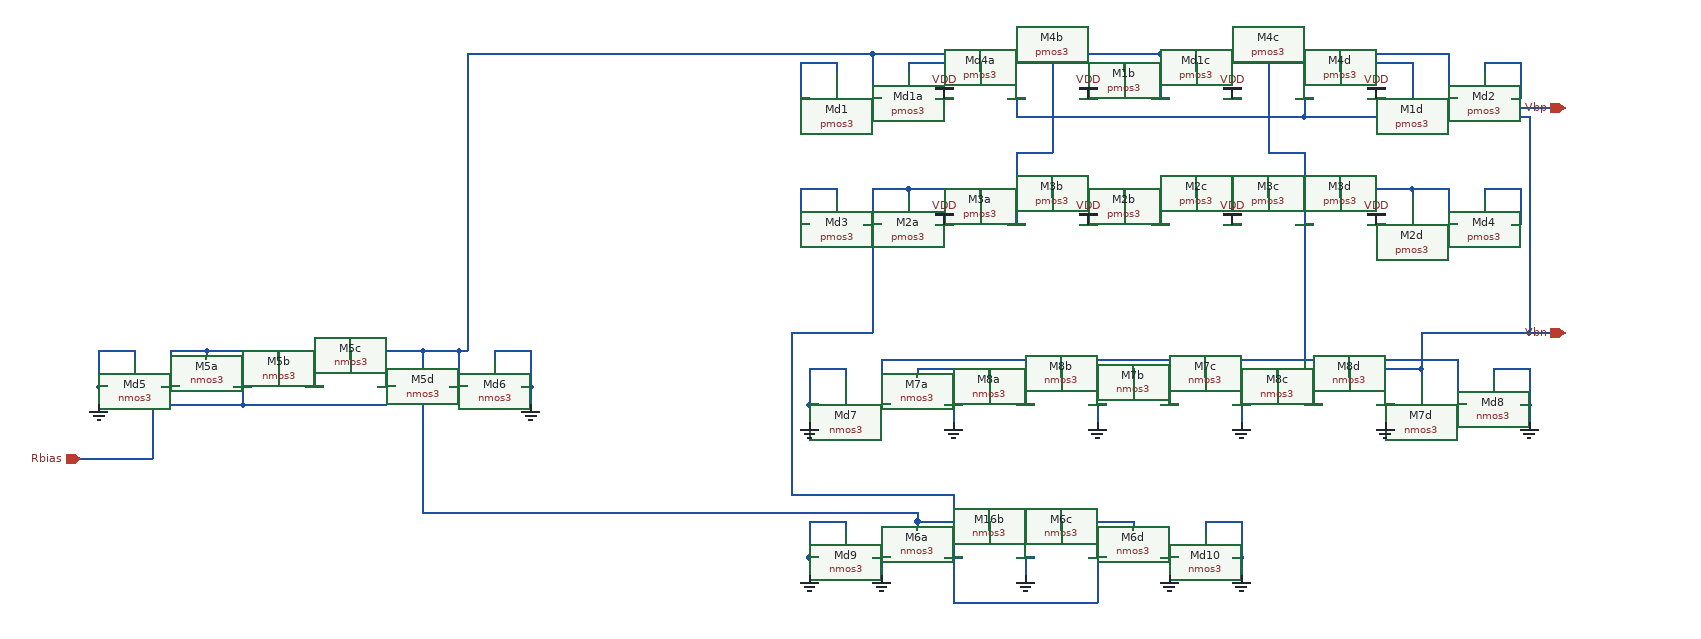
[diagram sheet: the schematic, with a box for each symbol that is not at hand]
v {xschem version=2.9.9 file_version=1.2 }
G {}
K {}
V {}
S {}
E {}
N 660 -1080 680 -1080 { lab=Rbias}
N 580 -1080 600 -1080 { lab=#net1}
N 500 -1080 520 -1080 { lab=Rbias}
N 710 -1120 710 -1110 { lab=#net1}
N 470 -1120 710 -1120 { lab=#net1}
N 470 -1120 470 -1110 { lab=#net1}
N 550 -1120 550 -1110 { lab=#net1}
N 630 -1120 630 -1110 { lab=#net1}
N 670 -1080 670 -1060 { lab=Rbias}
N 510 -1060 670 -1060 { lab=Rbias}
N 510 -1080 510 -1060 { lab=Rbias}
N 410 -1060 510 -1060 { lab=Rbias}
N 430 -1080 440 -1080 { lab=#net1}
N 740 -1080 750 -1080 { lab=#net1}
N 430 -1120 470 -1120 { lab=#net1}
N 430 -1120 430 -1080 { lab=#net1}
N 710 -1120 750 -1120 { lab=#net1}
N 750 -1120 750 -1080 { lab=#net1}
N 590 -1120 590 -1080 { lab=#net1}
N 760 -1210 760 -1120 { lab=#net1}
N 750 -1120 760 -1120 { lab=#net1}
N 750 -1080 760 -1080 { lab=#net1}
N 790 -1120 790 -1110 { lab=GND}
N 790 -1120 830 -1120 { lab=GND}
N 830 -1120 830 -1080 { lab=GND}
N 820 -1080 830 -1080 { lab=GND}
N 830 -1080 830 -1060 { lab=GND}
N 420 -1080 430 -1080 { lab=#net1}
N 390 -1120 390 -1110 { lab=GND}
N 360 -1120 390 -1120 { lab=GND}
N 350 -1080 360 -1080 { lab=GND}
N 350 -1120 360 -1120 { lab=GND}
N 350 -1120 350 -1080 { lab=GND}
N 350 -1080 350 -1060 { lab=GND}
N 410 -1060 410 -1000 { lab=Rbias}
N 330 -1000 410 -1000 { lab=Rbias}
N 1180 -1100 1180 -1090 { lab=GND}
N 1260 -1100 1260 -1090 { lab=Vbp}
N 1340 -1100 1340 -1090 { lab=Vbp}
N 1420 -1100 1420 -1090 { lab=Vbp}
N 1210 -1060 1230 -1060 { lab=Vbp}
N 1290 -1060 1310 -1060 { lab=GND}
N 1370 -1060 1390 -1060 { lab=Vbp}
N 1450 -1060 1470 -1060 { lab=GND}
N 1500 -1100 1500 -1090 { lab=Vbp}
N 1580 -1100 1580 -1090 { lab=Vbp}
N 1660 -1100 1660 -1090 { lab=Vbp}
N 1740 -1100 1740 -1090 { lab=Vbp}
N 1530 -1060 1550 -1060 { lab=Vbp}
N 1610 -1060 1630 -1060 { lab=GND}
N 1690 -1060 1710 -1060 { lab=Vbp}
N 1770 -1060 1790 -1060 { lab=GND}
N 1820 -1100 1820 -1090 { lab=Vbp}
N 1900 -1100 1900 -1090 { lab=GND}
N 1850 -1060 1870 -1060 { lab=Vbp}
N 1260 -1100 1820 -1100 { lab=Vbp}
N 1140 -1100 1180 -1100 { lab=GND}
N 1140 -1100 1140 -1060 { lab=GND}
N 1140 -1060 1150 -1060 { lab=GND}
N 1930 -1060 1940 -1060 { lab=GND}
N 1940 -1100 1940 -1060 { lab=GND}
N 1900 -1100 1940 -1100 { lab=GND}
N 1940 -1060 1940 -1040 { lab=GND}
N 1140 -1060 1140 -1040 { lab=GND}
N 1300 -1060 1300 -1040 { lab=GND}
N 1460 -1060 1460 -1040 { lab=GND}
N 1620 -1060 1620 -1040 { lab=GND}
N 1780 -1060 1780 -1040 { lab=GND}
N 1380 -1100 1380 -1060 { lab=Vbp}
N 1700 -1100 1700 -1060 { lab=Vbp}
N 1220 -1110 1220 -1060 { lab=Vbp}
N 1220 -1110 1860 -1110 { lab=Vbp}
N 1860 -1110 1860 -1060 { lab=Vbp}
N 1540 -1110 1540 -1060 { lab=Vbp}
N 1200 -1400 1220 -1400 { lab=#net1}
N 1280 -1400 1300 -1400 { lab=VDD}
N 1360 -1400 1380 -1400 { lab=Vbp}
N 1440 -1400 1460 -1400 { lab=VDD}
N 1520 -1400 1540 -1400 { lab=#net1}
N 1600 -1400 1620 -1400 { lab=VDD}
N 1680 -1400 1700 -1400 { lab=Vbp}
N 1760 -1400 1780 -1400 { lab=VDD}
N 1840 -1400 1860 -1400 { lab=#net1}
N 1170 -1440 1170 -1430 { lab=#net2}
N 1250 -1440 1250 -1430 { lab=Vbp}
N 1330 -1440 1330 -1430 { lab=Vbp}
N 1410 -1440 1410 -1430 { lab=Vbp}
N 1490 -1440 1490 -1430 { lab=Vbp}
N 1570 -1440 1570 -1430 { lab=Vbp}
N 1650 -1440 1650 -1430 { lab=Vbp}
N 1730 -1440 1730 -1430 { lab=Vbp}
N 1810 -1440 1810 -1430 { lab=Vbp}
N 1890 -1440 1890 -1430 { lab=#net3}
N 1250 -1440 1810 -1440 { lab=Vbp}
N 1890 -1440 1930 -1440 { lab=#net3}
N 1930 -1440 1930 -1400 { lab=#net3}
N 1920 -1400 1930 -1400 { lab=#net3}
N 1130 -1440 1170 -1440 { lab=#net2}
N 1130 -1440 1130 -1400 { lab=#net2}
N 1130 -1400 1140 -1400 { lab=#net2}
N 1200 -1260 1220 -1260 { lab=#net4}
N 1280 -1260 1300 -1260 { lab=VDD}
N 1360 -1260 1380 -1260 { lab=Vbp}
N 1440 -1260 1460 -1260 { lab=VDD}
N 1520 -1260 1540 -1260 { lab=#net4}
N 1600 -1260 1620 -1260 { lab=VDD}
N 1680 -1260 1700 -1260 { lab=Vbp}
N 1760 -1260 1780 -1260 { lab=VDD}
N 1840 -1260 1860 -1260 { lab=#net4}
N 1170 -1300 1170 -1290 { lab=#net5}
N 1250 -1300 1250 -1290 { lab=#net4}
N 1330 -1300 1330 -1290 { lab=#net4}
N 1410 -1300 1410 -1290 { lab=#net4}
N 1490 -1300 1490 -1290 { lab=#net4}
N 1570 -1300 1570 -1290 { lab=#net4}
N 1650 -1300 1650 -1290 { lab=#net4}
N 1730 -1300 1730 -1290 { lab=#net4}
N 1810 -1300 1810 -1290 { lab=#net4}
N 1890 -1300 1890 -1290 { lab=#net6}
N 1250 -1300 1810 -1300 { lab=#net4}
N 1890 -1300 1930 -1300 { lab=#net6}
N 1930 -1300 1930 -1260 { lab=#net6}
N 1920 -1260 1930 -1260 { lab=#net6}
N 1130 -1300 1170 -1300 { lab=#net5}
N 1130 -1300 1130 -1260 { lab=#net5}
N 1130 -1260 1140 -1260 { lab=#net5}
N 1530 -1450 1530 -1400 { lab=#net1}
N 1210 -1450 1530 -1450 { lab=#net1}
N 1210 -1450 1210 -1400 { lab=#net1}
N 1850 -1450 1850 -1400 { lab=#net1}
N 1530 -1450 1850 -1450 { lab=#net1}
N 1530 -1300 1530 -1260 { lab=#net4}
N 1210 -1300 1210 -1260 { lab=#net4}
N 1210 -1300 1250 -1300 { lab=#net4}
N 1850 -1300 1850 -1260 { lab=#net4}
N 1810 -1300 1850 -1300 { lab=#net4}
N 1370 -1340 1370 -1260 { lab=Vbp}
N 1370 -1340 1410 -1340 { lab=Vbp}
N 1410 -1430 1410 -1340 { lab=Vbp}
N 1690 -1340 1690 -1260 { lab=Vbp}
N 1650 -1340 1690 -1340 { lab=Vbp}
N 1650 -1430 1650 -1340 { lab=Vbp}
N 1370 -1400 1370 -1380 { lab=Vbp}
N 1370 -1380 1690 -1380 { lab=Vbp}
N 1690 -1400 1690 -1380 { lab=Vbp}
N 1290 -890 1310 -890 { lab=#net4}
N 1370 -890 1390 -890 { lab=GND}
N 1450 -890 1470 -890 { lab=#net4}
N 1500 -930 1500 -920 { lab=#net1}
N 1420 -930 1420 -920 { lab=#net1}
N 1340 -930 1340 -920 { lab=#net1}
N 1260 -930 1260 -920 { lab=#net1}
N 1260 -930 1500 -930 { lab=#net1}
N 1530 -890 1550 -890 { lab=GND}
N 1210 -890 1230 -890 { lab=GND}
N 1180 -930 1180 -920 { lab=GND}
N 1140 -930 1180 -930 { lab=GND}
N 1140 -930 1140 -890 { lab=GND}
N 1140 -890 1150 -890 { lab=GND}
N 1580 -930 1580 -920 { lab=GND}
N 1580 -930 1620 -930 { lab=GND}
N 1620 -930 1620 -890 { lab=GND}
N 1610 -890 1620 -890 { lab=GND}
N 1210 -1260 1210 -1220 { lab=#net4}
N 1690 -1260 1690 -1210 { lab=Vbp}
N 1690 -1380 1940 -1380 { lab=Vbp}
N 1940 -1380 1940 -1210 { lab=Vbp}
N 760 -1450 1210 -1450 { lab=#net1}
N 760 -1450 760 -1210 { lab=#net1}
N 1620 -890 1620 -870 { lab=GND}
N 1540 -890 1540 -870 { lab=GND}
N 1380 -890 1380 -870 { lab=GND}
N 1220 -890 1220 -870 { lab=GND}
N 1140 -890 1140 -870 { lab=GND}
N 1460 -890 1460 -840 { lab=#net4}
N 1300 -840 1460 -840 { lab=#net4}
N 1300 -890 1300 -840 { lab=#net4}
N 1690 -1210 1690 -1110 { lab=Vbp}
N 1820 -1140 1820 -1100 { lab=Vbp}
N 1820 -1140 1940 -1140 { lab=Vbp}
N 1940 -1210 1940 -1140 { lab=Vbp}
N 1210 -1220 1210 -1140 { lab=#net4}
N 1120 -1140 1210 -1140 { lab=#net4}
N 1120 -1140 1120 -960 { lab=#net4}
N 1120 -960 1300 -960 { lab=#net4}
N 1300 -960 1300 -890 { lab=#net4}
N 1260 -940 1260 -930 { lab=#net1}
N 710 -940 1260 -940 { lab=#net1}
N 710 -1110 710 -940 { lab=#net1}
N 1810 -1430 1810 -1390 { lab=Vbp}
N 1810 -1390 1980 -1390 { lab=Vbp}
N 1940 -1140 1980 -1140 { lab=Vbp}
C {madvlsi/nmos3.sym} 470 -1080 1 0 {name=M5a
L=0.5
W=1.4*2
body=GND
nf=1
mult=1
ad="'int((nf+1)/2) * W/nf * 0.29'" 
pd="'2*int((nf+1)/2) * (W/nf + 0.29)'"
as="'int((nf+2)/2) * W/nf * 0.29'" 
ps="'2*int((nf+2)/2) * (W/nf + 0.29)'"
nrd="'0.29 / W'" nrs="'0.29 / W'"
sa=0 sb=0 sd=0
model=nfet_01v8
spiceprefix=X
}
C {madvlsi/nmos3.sym} 550 -1080 1 0 {name=M5b
L=0.5
W=1.4*2
body=GND
nf=1
mult=1
ad="'int((nf+1)/2) * W/nf * 0.29'" 
pd="'2*int((nf+1)/2) * (W/nf + 0.29)'"
as="'int((nf+2)/2) * W/nf * 0.29'" 
ps="'2*int((nf+2)/2) * (W/nf + 0.29)'"
nrd="'0.29 / W'" nrs="'0.29 / W'"
sa=0 sb=0 sd=0
model=nfet_01v8
spiceprefix=X
}
C {madvlsi/nmos3.sym} 630 -1080 1 0 {name=M5c
L=0.5
W=1.4*2
body=GND
nf=1
mult=1
ad="'int((nf+1)/2) * W/nf * 0.29'" 
pd="'2*int((nf+1)/2) * (W/nf + 0.29)'"
as="'int((nf+2)/2) * W/nf * 0.29'" 
ps="'2*int((nf+2)/2) * (W/nf + 0.29)'"
nrd="'0.29 / W'" nrs="'0.29 / W'"
sa=0 sb=0 sd=0
model=nfet_01v8
spiceprefix=X
}
C {madvlsi/nmos3.sym} 710 -1080 1 0 {name=M5d
L=0.5
W=1.4*2
body=GND
nf=1
mult=1
ad="'int((nf+1)/2) * W/nf * 0.29'" 
pd="'2*int((nf+1)/2) * (W/nf + 0.29)'"
as="'int((nf+2)/2) * W/nf * 0.29'" 
ps="'2*int((nf+2)/2) * (W/nf + 0.29)'"
nrd="'0.29 / W'" nrs="'0.29 / W'"
sa=0 sb=0 sd=0
model=nfet_01v8
spiceprefix=X
}
C {madvlsi/nmos3.sym} 790 -1080 1 0 {name=Md6
L=0.5
W=1.4*2
body=GND
nf=1
mult=1
ad="'int((nf+1)/2) * W/nf * 0.29'" 
pd="'2*int((nf+1)/2) * (W/nf + 0.29)'"
as="'int((nf+2)/2) * W/nf * 0.29'" 
ps="'2*int((nf+2)/2) * (W/nf + 0.29)'"
nrd="'0.29 / W'" nrs="'0.29 / W'"
sa=0 sb=0 sd=0
model=nfet_01v8
spiceprefix=X
}
C {madvlsi/nmos3.sym} 390 -1080 1 0 {name=Md5
L=0.5
W=1.4*2
body=GND
nf=1
mult=1
ad="'int((nf+1)/2) * W/nf * 0.29'" 
pd="'2*int((nf+1)/2) * (W/nf + 0.29)'"
as="'int((nf+2)/2) * W/nf * 0.29'" 
ps="'2*int((nf+2)/2) * (W/nf + 0.29)'"
nrd="'0.29 / W'" nrs="'0.29 / W'"
sa=0 sb=0 sd=0
model=nfet_01v8
spiceprefix=X
}
C {madvlsi/gnd.sym} 350 -1060 0 0 {name=l11 lab=GND}
C {madvlsi/gnd.sym} 830 -1060 0 0 {name=l12 lab=GND}
C {devices/iopin.sym} 330 -1000 2 0 {name=p1 lab=Rbias}
C {madvlsi/nmos3.sym} 1180 -1060 1 0 {name=Md7
L=0.5
W=1.4/4
body=GND
nf=1
mult=1
ad="'int((nf+1)/2) * W/nf * 0.29'" 
pd="'2*int((nf+1)/2) * (W/nf + 0.29)'"
as="'int((nf+2)/2) * W/nf * 0.29'" 
ps="'2*int((nf+2)/2) * (W/nf + 0.29)'"
nrd="'0.29 / W'" nrs="'0.29 / W'"
sa=0 sb=0 sd=0
model=nfet_01v8
spiceprefix=X
}
C {madvlsi/nmos3.sym} 1260 -1060 1 0 {name=M7a
L=0.5
W=1.4/4
body=GND
nf=1
mult=1
ad="'int((nf+1)/2) * W/nf * 0.29'" 
pd="'2*int((nf+1)/2) * (W/nf + 0.29)'"
as="'int((nf+2)/2) * W/nf * 0.29'" 
ps="'2*int((nf+2)/2) * (W/nf + 0.29)'"
nrd="'0.29 / W'" nrs="'0.29 / W'"
sa=0 sb=0 sd=0
model=nfet_01v8
spiceprefix=X
}
C {madvlsi/nmos3.sym} 1340 -1060 1 0 {name=M8a
L=0.5
W=1.4/4
body=GND
nf=1
mult=1
ad="'int((nf+1)/2) * W/nf * 0.29'" 
pd="'2*int((nf+1)/2) * (W/nf + 0.29)'"
as="'int((nf+2)/2) * W/nf * 0.29'" 
ps="'2*int((nf+2)/2) * (W/nf + 0.29)'"
nrd="'0.29 / W'" nrs="'0.29 / W'"
sa=0 sb=0 sd=0
model=nfet_01v8
spiceprefix=X
}
C {madvlsi/nmos3.sym} 1420 -1060 1 0 {name=M8b
L=0.5
W=1.4/4
body=GND
nf=1
mult=1
ad="'int((nf+1)/2) * W/nf * 0.29'" 
pd="'2*int((nf+1)/2) * (W/nf + 0.29)'"
as="'int((nf+2)/2) * W/nf * 0.29'" 
ps="'2*int((nf+2)/2) * (W/nf + 0.29)'"
nrd="'0.29 / W'" nrs="'0.29 / W'"
sa=0 sb=0 sd=0
model=nfet_01v8
spiceprefix=X
}
C {madvlsi/nmos3.sym} 1500 -1060 1 0 {name=M7b
L=0.5
W=1.4/4
body=GND
nf=1
mult=1
ad="'int((nf+1)/2) * W/nf * 0.29'" 
pd="'2*int((nf+1)/2) * (W/nf + 0.29)'"
as="'int((nf+2)/2) * W/nf * 0.29'" 
ps="'2*int((nf+2)/2) * (W/nf + 0.29)'"
nrd="'0.29 / W'" nrs="'0.29 / W'"
sa=0 sb=0 sd=0
model=nfet_01v8
spiceprefix=X
}
C {madvlsi/nmos3.sym} 1580 -1060 1 0 {name=M7c
L=0.5
W=1.4/4
body=GND
nf=1
mult=1
ad="'int((nf+1)/2) * W/nf * 0.29'" 
pd="'2*int((nf+1)/2) * (W/nf + 0.29)'"
as="'int((nf+2)/2) * W/nf * 0.29'" 
ps="'2*int((nf+2)/2) * (W/nf + 0.29)'"
nrd="'0.29 / W'" nrs="'0.29 / W'"
sa=0 sb=0 sd=0
model=nfet_01v8
spiceprefix=X
}
C {madvlsi/nmos3.sym} 1660 -1060 1 0 {name=M8c
L=0.5
W=1.4/4
body=GND
nf=1
mult=1
ad="'int((nf+1)/2) * W/nf * 0.29'" 
pd="'2*int((nf+1)/2) * (W/nf + 0.29)'"
as="'int((nf+2)/2) * W/nf * 0.29'" 
ps="'2*int((nf+2)/2) * (W/nf + 0.29)'"
nrd="'0.29 / W'" nrs="'0.29 / W'"
sa=0 sb=0 sd=0
model=nfet_01v8
spiceprefix=X
}
C {madvlsi/nmos3.sym} 1740 -1060 1 0 {name=M8d
L=0.5
W=1.4/4
body=GND
nf=1
mult=1
ad="'int((nf+1)/2) * W/nf * 0.29'" 
pd="'2*int((nf+1)/2) * (W/nf + 0.29)'"
as="'int((nf+2)/2) * W/nf * 0.29'" 
ps="'2*int((nf+2)/2) * (W/nf + 0.29)'"
nrd="'0.29 / W'" nrs="'0.29 / W'"
sa=0 sb=0 sd=0
model=nfet_01v8
spiceprefix=X
}
C {madvlsi/nmos3.sym} 1820 -1060 1 0 {name=M7d
L=0.5
W=1.4/4
body=GND
nf=1
mult=1
ad="'int((nf+1)/2) * W/nf * 0.29'" 
pd="'2*int((nf+1)/2) * (W/nf + 0.29)'"
as="'int((nf+2)/2) * W/nf * 0.29'" 
ps="'2*int((nf+2)/2) * (W/nf + 0.29)'"
nrd="'0.29 / W'" nrs="'0.29 / W'"
sa=0 sb=0 sd=0
model=nfet_01v8
spiceprefix=X
}
C {madvlsi/nmos3.sym} 1900 -1060 1 0 {name=Md8
L=0.5
W=1.4/4
body=GND
nf=1
mult=1
ad="'int((nf+1)/2) * W/nf * 0.29'" 
pd="'2*int((nf+1)/2) * (W/nf + 0.29)'"
as="'int((nf+2)/2) * W/nf * 0.29'" 
ps="'2*int((nf+2)/2) * (W/nf + 0.29)'"
nrd="'0.29 / W'" nrs="'0.29 / W'"
sa=0 sb=0 sd=0
model=nfet_01v8
spiceprefix=X
}
C {madvlsi/gnd.sym} 1140 -1040 0 0 {name=l13 lab=GND}
C {madvlsi/gnd.sym} 1940 -1040 0 0 {name=l14 lab=GND}
C {madvlsi/gnd.sym} 1300 -1040 0 0 {name=l15 lab=GND}
C {madvlsi/gnd.sym} 1460 -1040 0 0 {name=l16 lab=GND}
C {madvlsi/gnd.sym} 1620 -1040 0 0 {name=l17 lab=GND}
C {madvlsi/gnd.sym} 1780 -1040 0 0 {name=l18 lab=GND}
C {madvlsi/pmos3.sym} 1170 -1400 1 0 {name=Md1
L=0.5
W=1.4/4
body=VDD
nf=1
mult=1
ad="'int((nf+1)/2) * W/nf * 0.29'" 
pd="'2*int((nf+1)/2) * (W/nf + 0.29)'"
as="'int((nf+2)/2) * W/nf * 0.29'" 
ps="'2*int((nf+2)/2) * (W/nf + 0.29)'"
nrd="'0.29 / W'" nrs="'0.29 / W'"
sa=0 sb=0 sd=0
model=pfet_01v8
spiceprefix=X
}
C {madvlsi/pmos3.sym} 1250 -1400 1 0 {name=Md1a
L=0.5
W=1.4/4
body=VDD
nf=1
mult=1
ad="'int((nf+1)/2) * W/nf * 0.29'" 
pd="'2*int((nf+1)/2) * (W/nf + 0.29)'"
as="'int((nf+2)/2) * W/nf * 0.29'" 
ps="'2*int((nf+2)/2) * (W/nf + 0.29)'"
nrd="'0.29 / W'" nrs="'0.29 / W'"
sa=0 sb=0 sd=0
model=pfet_01v8
spiceprefix=X
}
C {madvlsi/pmos3.sym} 1330 -1400 1 0 {name=Md4a
L=0.5
W=1.4/4
body=VDD
nf=1
mult=1
ad="'int((nf+1)/2) * W/nf * 0.29'" 
pd="'2*int((nf+1)/2) * (W/nf + 0.29)'"
as="'int((nf+2)/2) * W/nf * 0.29'" 
ps="'2*int((nf+2)/2) * (W/nf + 0.29)'"
nrd="'0.29 / W'" nrs="'0.29 / W'"
sa=0 sb=0 sd=0
model=pfet_01v8
spiceprefix=X
}
C {madvlsi/pmos3.sym} 1410 -1400 1 0 {name=M4b
L=0.5
W=1.4/4
body=VDD
nf=1
mult=1
ad="'int((nf+1)/2) * W/nf * 0.29'" 
pd="'2*int((nf+1)/2) * (W/nf + 0.29)'"
as="'int((nf+2)/2) * W/nf * 0.29'" 
ps="'2*int((nf+2)/2) * (W/nf + 0.29)'"
nrd="'0.29 / W'" nrs="'0.29 / W'"
sa=0 sb=0 sd=0
model=pfet_01v8
spiceprefix=X
}
C {madvlsi/pmos3.sym} 1490 -1400 1 0 {name=M1b
L=0.5
W=1.4/4
body=VDD
nf=1
mult=1
ad="'int((nf+1)/2) * W/nf * 0.29'" 
pd="'2*int((nf+1)/2) * (W/nf + 0.29)'"
as="'int((nf+2)/2) * W/nf * 0.29'" 
ps="'2*int((nf+2)/2) * (W/nf + 0.29)'"
nrd="'0.29 / W'" nrs="'0.29 / W'"
sa=0 sb=0 sd=0
model=pfet_01v8
spiceprefix=X
}
C {madvlsi/pmos3.sym} 1570 -1400 1 0 {name=Md1c
L=0.5
W=1.4/4
body=VDD
nf=1
mult=1
ad="'int((nf+1)/2) * W/nf * 0.29'" 
pd="'2*int((nf+1)/2) * (W/nf + 0.29)'"
as="'int((nf+2)/2) * W/nf * 0.29'" 
ps="'2*int((nf+2)/2) * (W/nf + 0.29)'"
nrd="'0.29 / W'" nrs="'0.29 / W'"
sa=0 sb=0 sd=0
model=pfet_01v8
spiceprefix=X
}
C {madvlsi/pmos3.sym} 1650 -1400 1 0 {name=M4c
L=0.5
W=1.4/4
body=VDD
nf=1
mult=1
ad="'int((nf+1)/2) * W/nf * 0.29'" 
pd="'2*int((nf+1)/2) * (W/nf + 0.29)'"
as="'int((nf+2)/2) * W/nf * 0.29'" 
ps="'2*int((nf+2)/2) * (W/nf + 0.29)'"
nrd="'0.29 / W'" nrs="'0.29 / W'"
sa=0 sb=0 sd=0
model=pfet_01v8
spiceprefix=X
}
C {madvlsi/pmos3.sym} 1730 -1400 1 0 {name=M4d
L=0.5
W=1.4/4
body=VDD
nf=1
mult=1
ad="'int((nf+1)/2) * W/nf * 0.29'" 
pd="'2*int((nf+1)/2) * (W/nf + 0.29)'"
as="'int((nf+2)/2) * W/nf * 0.29'" 
ps="'2*int((nf+2)/2) * (W/nf + 0.29)'"
nrd="'0.29 / W'" nrs="'0.29 / W'"
sa=0 sb=0 sd=0
model=pfet_01v8
spiceprefix=X
}
C {madvlsi/pmos3.sym} 1810 -1400 1 0 {name=M1d
L=0.5
W=1.4/4
body=VDD
nf=1
mult=1
ad="'int((nf+1)/2) * W/nf * 0.29'" 
pd="'2*int((nf+1)/2) * (W/nf + 0.29)'"
as="'int((nf+2)/2) * W/nf * 0.29'" 
ps="'2*int((nf+2)/2) * (W/nf + 0.29)'"
nrd="'0.29 / W'" nrs="'0.29 / W'"
sa=0 sb=0 sd=0
model=pfet_01v8
spiceprefix=X
}
C {madvlsi/pmos3.sym} 1890 -1400 1 0 {name=Md2
L=0.5
W=1.4/4
body=VDD
nf=1
mult=1
ad="'int((nf+1)/2) * W/nf * 0.29'" 
pd="'2*int((nf+1)/2) * (W/nf + 0.29)'"
as="'int((nf+2)/2) * W/nf * 0.29'" 
ps="'2*int((nf+2)/2) * (W/nf + 0.29)'"
nrd="'0.29 / W'" nrs="'0.29 / W'"
sa=0 sb=0 sd=0
model=pfet_01v8
spiceprefix=X
}
C {madvlsi/pmos3.sym} 1170 -1260 1 0 {name=Md3
L=0.5
W=1.4/4
body=VDD
nf=1
mult=1
ad="'int((nf+1)/2) * W/nf * 0.29'" 
pd="'2*int((nf+1)/2) * (W/nf + 0.29)'"
as="'int((nf+2)/2) * W/nf * 0.29'" 
ps="'2*int((nf+2)/2) * (W/nf + 0.29)'"
nrd="'0.29 / W'" nrs="'0.29 / W'"
sa=0 sb=0 sd=0
model=pfet_01v8
spiceprefix=X
}
C {madvlsi/pmos3.sym} 1250 -1260 1 0 {name=M2a
L=0.5
W=1.4/4
body=VDD
nf=1
mult=1
ad="'int((nf+1)/2) * W/nf * 0.29'" 
pd="'2*int((nf+1)/2) * (W/nf + 0.29)'"
as="'int((nf+2)/2) * W/nf * 0.29'" 
ps="'2*int((nf+2)/2) * (W/nf + 0.29)'"
nrd="'0.29 / W'" nrs="'0.29 / W'"
sa=0 sb=0 sd=0
model=pfet_01v8
spiceprefix=X
}
C {madvlsi/pmos3.sym} 1330 -1260 1 0 {name=M3a
L=0.5
W=1.4/4
body=VDD
nf=1
mult=1
ad="'int((nf+1)/2) * W/nf * 0.29'" 
pd="'2*int((nf+1)/2) * (W/nf + 0.29)'"
as="'int((nf+2)/2) * W/nf * 0.29'" 
ps="'2*int((nf+2)/2) * (W/nf + 0.29)'"
nrd="'0.29 / W'" nrs="'0.29 / W'"
sa=0 sb=0 sd=0
model=pfet_01v8
spiceprefix=X
}
C {madvlsi/pmos3.sym} 1410 -1260 1 0 {name=M3b
L=0.5
W=1.4/4
body=VDD
nf=1
mult=1
ad="'int((nf+1)/2) * W/nf * 0.29'" 
pd="'2*int((nf+1)/2) * (W/nf + 0.29)'"
as="'int((nf+2)/2) * W/nf * 0.29'" 
ps="'2*int((nf+2)/2) * (W/nf + 0.29)'"
nrd="'0.29 / W'" nrs="'0.29 / W'"
sa=0 sb=0 sd=0
model=pfet_01v8
spiceprefix=X
}
C {madvlsi/pmos3.sym} 1490 -1260 1 0 {name=M2b
L=0.5
W=1.4/4
body=VDD
nf=1
mult=1
ad="'int((nf+1)/2) * W/nf * 0.29'" 
pd="'2*int((nf+1)/2) * (W/nf + 0.29)'"
as="'int((nf+2)/2) * W/nf * 0.29'" 
ps="'2*int((nf+2)/2) * (W/nf + 0.29)'"
nrd="'0.29 / W'" nrs="'0.29 / W'"
sa=0 sb=0 sd=0
model=pfet_01v8
spiceprefix=X
}
C {madvlsi/pmos3.sym} 1570 -1260 1 0 {name=M2c
L=0.5
W=1.4/4
body=VDD
nf=1
mult=1
ad="'int((nf+1)/2) * W/nf * 0.29'" 
pd="'2*int((nf+1)/2) * (W/nf + 0.29)'"
as="'int((nf+2)/2) * W/nf * 0.29'" 
ps="'2*int((nf+2)/2) * (W/nf + 0.29)'"
nrd="'0.29 / W'" nrs="'0.29 / W'"
sa=0 sb=0 sd=0
model=pfet_01v8
spiceprefix=X
}
C {madvlsi/pmos3.sym} 1650 -1260 1 0 {name=M3c
L=0.5
W=1.4/4
body=VDD
nf=1
mult=1
ad="'int((nf+1)/2) * W/nf * 0.29'" 
pd="'2*int((nf+1)/2) * (W/nf + 0.29)'"
as="'int((nf+2)/2) * W/nf * 0.29'" 
ps="'2*int((nf+2)/2) * (W/nf + 0.29)'"
nrd="'0.29 / W'" nrs="'0.29 / W'"
sa=0 sb=0 sd=0
model=pfet_01v8
spiceprefix=X
}
C {madvlsi/pmos3.sym} 1730 -1260 1 0 {name=M3d
L=0.5
W=1.4/4
body=VDD
nf=1
mult=1
ad="'int((nf+1)/2) * W/nf * 0.29'" 
pd="'2*int((nf+1)/2) * (W/nf + 0.29)'"
as="'int((nf+2)/2) * W/nf * 0.29'" 
ps="'2*int((nf+2)/2) * (W/nf + 0.29)'"
nrd="'0.29 / W'" nrs="'0.29 / W'"
sa=0 sb=0 sd=0
model=pfet_01v8
spiceprefix=X
}
C {madvlsi/pmos3.sym} 1810 -1260 1 0 {name=M2d
L=0.5
W=1.4/4
body=VDD
nf=1
mult=1
ad="'int((nf+1)/2) * W/nf * 0.29'" 
pd="'2*int((nf+1)/2) * (W/nf + 0.29)'"
as="'int((nf+2)/2) * W/nf * 0.29'" 
ps="'2*int((nf+2)/2) * (W/nf + 0.29)'"
nrd="'0.29 / W'" nrs="'0.29 / W'"
sa=0 sb=0 sd=0
model=pfet_01v8
spiceprefix=X
}
C {madvlsi/pmos3.sym} 1890 -1260 1 0 {name=Md4
L=0.5
W=1.4/4
body=VDD
nf=1
mult=1
ad="'int((nf+1)/2) * W/nf * 0.29'" 
pd="'2*int((nf+1)/2) * (W/nf + 0.29)'"
as="'int((nf+2)/2) * W/nf * 0.29'" 
ps="'2*int((nf+2)/2) * (W/nf + 0.29)'"
nrd="'0.29 / W'" nrs="'0.29 / W'"
sa=0 sb=0 sd=0
model=pfet_01v8
spiceprefix=X
}
C {madvlsi/vdd.sym} 1610 -1400 0 0 {name=l1 lab=VDD}
C {madvlsi/vdd.sym} 1450 -1400 0 0 {name=l2 lab=VDD}
C {madvlsi/vdd.sym} 1290 -1400 0 0 {name=l3 lab=VDD}
C {madvlsi/vdd.sym} 1770 -1400 0 0 {name=l4 lab=VDD}
C {madvlsi/vdd.sym} 1450 -1260 0 0 {name=l5 lab=VDD}
C {madvlsi/vdd.sym} 1610 -1260 0 0 {name=l6 lab=VDD}
C {madvlsi/vdd.sym} 1770 -1260 0 0 {name=l7 lab=VDD}
C {madvlsi/vdd.sym} 1290 -1260 0 0 {name=l8 lab=VDD}
C {madvlsi/nmos3.sym} 1260 -890 1 0 {name=M6a
L=0.5
W=1.4/4
body=GND
nf=1
mult=1
ad="'int((nf+1)/2) * W/nf * 0.29'" 
pd="'2*int((nf+1)/2) * (W/nf + 0.29)'"
as="'int((nf+2)/2) * W/nf * 0.29'" 
ps="'2*int((nf+2)/2) * (W/nf + 0.29)'"
nrd="'0.29 / W'" nrs="'0.29 / W'"
sa=0 sb=0 sd=0
model=nfet_01v8
spiceprefix=X
}
C {madvlsi/nmos3.sym} 1340 -890 1 0 {name=M16b
L=0.5
W=1.4/4
body=GND
nf=1
mult=1
ad="'int((nf+1)/2) * W/nf * 0.29'" 
pd="'2*int((nf+1)/2) * (W/nf + 0.29)'"
as="'int((nf+2)/2) * W/nf * 0.29'" 
ps="'2*int((nf+2)/2) * (W/nf + 0.29)'"
nrd="'0.29 / W'" nrs="'0.29 / W'"
sa=0 sb=0 sd=0
model=nfet_01v8
spiceprefix=X
}
C {madvlsi/nmos3.sym} 1420 -890 1 0 {name=M6c
L=0.5
W=1.4/4
body=GND
nf=1
mult=1
ad="'int((nf+1)/2) * W/nf * 0.29'" 
pd="'2*int((nf+1)/2) * (W/nf + 0.29)'"
as="'int((nf+2)/2) * W/nf * 0.29'" 
ps="'2*int((nf+2)/2) * (W/nf + 0.29)'"
nrd="'0.29 / W'" nrs="'0.29 / W'"
sa=0 sb=0 sd=0
model=nfet_01v8
spiceprefix=X
}
C {madvlsi/nmos3.sym} 1500 -890 1 0 {name=M6d
L=0.5
W=1.4/4
body=GND
nf=1
mult=1
ad="'int((nf+1)/2) * W/nf * 0.29'" 
pd="'2*int((nf+1)/2) * (W/nf + 0.29)'"
as="'int((nf+2)/2) * W/nf * 0.29'" 
ps="'2*int((nf+2)/2) * (W/nf + 0.29)'"
nrd="'0.29 / W'" nrs="'0.29 / W'"
sa=0 sb=0 sd=0
model=nfet_01v8
spiceprefix=X
}
C {madvlsi/nmos3.sym} 1180 -890 1 0 {name=Md9
L=0.5
W=1.4/4
body=GND
nf=1
mult=1
ad="'int((nf+1)/2) * W/nf * 0.29'" 
pd="'2*int((nf+1)/2) * (W/nf + 0.29)'"
as="'int((nf+2)/2) * W/nf * 0.29'" 
ps="'2*int((nf+2)/2) * (W/nf + 0.29)'"
nrd="'0.29 / W'" nrs="'0.29 / W'"
sa=0 sb=0 sd=0
model=nfet_01v8
spiceprefix=X
}
C {madvlsi/nmos3.sym} 1580 -890 1 0 {name=Md10
L=0.5
W=1.4/4
body=GND
nf=1
mult=1
ad="'int((nf+1)/2) * W/nf * 0.29'" 
pd="'2*int((nf+1)/2) * (W/nf + 0.29)'"
as="'int((nf+2)/2) * W/nf * 0.29'" 
ps="'2*int((nf+2)/2) * (W/nf + 0.29)'"
nrd="'0.29 / W'" nrs="'0.29 / W'"
sa=0 sb=0 sd=0
model=nfet_01v8
spiceprefix=X
}
C {madvlsi/gnd.sym} 1140 -870 0 0 {name=l9 lab=GND}
C {madvlsi/gnd.sym} 1220 -870 0 0 {name=l10 lab=GND}
C {madvlsi/gnd.sym} 1380 -870 0 0 {name=l19 lab=GND}
C {madvlsi/gnd.sym} 1540 -870 0 0 {name=l20 lab=GND}
C {madvlsi/gnd.sym} 1620 -870 0 0 {name=l21 lab=GND}
C {devices/iopin.sym} 1980 -1390 0 0 {name=p2 lab=Vbp}
C {devices/iopin.sym} 1980 -1140 0 0 {name=p3 lab=Vbn}
